# EOS mock tech LEF (v1). Synthetic layer data authored
# for CI; see gen_mock.py and mock/README.md.
VERSION 5.8 ;
BUSBITCHARS "[]" ;
DIVIDERCHAR "/" ;
UNITS
  DATABASE MICRONS 2000 ;
END UNITS
MANUFACTURINGGRID 0.005 ;
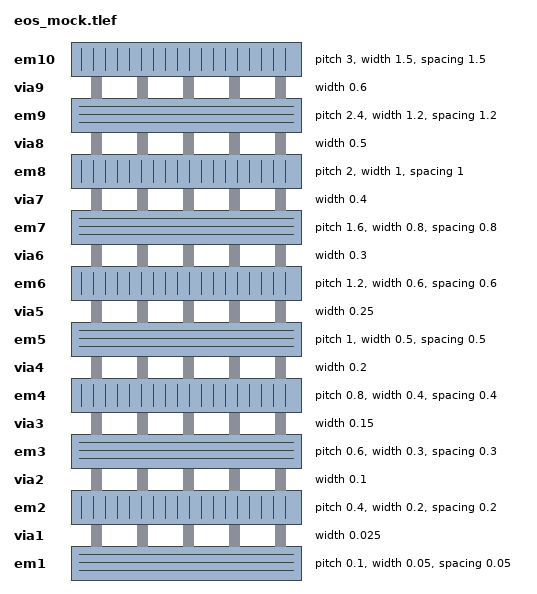
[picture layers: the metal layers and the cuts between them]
LAYER em1
  TYPE ROUTING ;
  DIRECTION HORIZONTAL ;
  PITCH 0.100000 ;
  WIDTH 0.050000 ;
  SPACING 0.050000 ;
  MINWIDTH 0.030000 ;
  AREA 0.005000 ;
  MINSTEP 0.100000 ;
  RESISTANCE RPERSQ 0.200000 ;
  CAPACITANCE CPERSQDIST 0.050000 ;
  EDGECAPACITANCE 0.020000 ;
END em1
LAYER via1
  TYPE CUT ;
  WIDTH 0.025000 ;
END via1
LAYER em2
  TYPE ROUTING ;
  DIRECTION VERTICAL ;
  PITCH 0.400000 ;
  WIDTH 0.200000 ;
  SPACING 0.200000 ;
  MINWIDTH 0.180000 ;
  AREA 0.020000 ;
  MINSTEP 0.100000 ;
  RESISTANCE RPERSQ 0.150000 ;
  CAPACITANCE CPERSQDIST 0.040000 ;
  EDGECAPACITANCE 0.015000 ;
END em2
LAYER via2
  TYPE CUT ;
  WIDTH 0.100000 ;
END via2
LAYER em3
  TYPE ROUTING ;
  DIRECTION HORIZONTAL ;
  PITCH 0.600000 ;
  WIDTH 0.300000 ;
  SPACING 0.300000 ;
  MINWIDTH 0.280000 ;
  AREA 0.030000 ;
  MINSTEP 0.100000 ;
  RESISTANCE RPERSQ 0.100000 ;
  CAPACITANCE CPERSQDIST 0.030000 ;
  EDGECAPACITANCE 0.012000 ;
END em3
LAYER via3
  TYPE CUT ;
  WIDTH 0.150000 ;
END via3
LAYER em4
  TYPE ROUTING ;
  DIRECTION VERTICAL ;
  PITCH 0.800000 ;
  WIDTH 0.400000 ;
  SPACING 0.400000 ;
  MINWIDTH 0.380000 ;
  AREA 0.040000 ;
  MINSTEP 0.100000 ;
  RESISTANCE RPERSQ 0.070000 ;
  CAPACITANCE CPERSQDIST 0.025000 ;
  EDGECAPACITANCE 0.010000 ;
END em4
LAYER via4
  TYPE CUT ;
  WIDTH 0.200000 ;
END via4
LAYER em5
  TYPE ROUTING ;
  DIRECTION HORIZONTAL ;
  PITCH 1.000000 ;
  WIDTH 0.500000 ;
  SPACING 0.500000 ;
  MINWIDTH 0.480000 ;
  AREA 0.050000 ;
  MINSTEP 0.100000 ;
  RESISTANCE RPERSQ 0.050000 ;
  CAPACITANCE CPERSQDIST 0.020000 ;
  EDGECAPACITANCE 0.008000 ;
END em5
LAYER via5
  TYPE CUT ;
  WIDTH 0.250000 ;
END via5
LAYER em6
  TYPE ROUTING ;
  DIRECTION VERTICAL ;
  PITCH 1.200000 ;
  WIDTH 0.600000 ;
  SPACING 0.600000 ;
  MINWIDTH 0.580000 ;
  AREA 0.060000 ;
  MINSTEP 0.100000 ;
  RESISTANCE RPERSQ 0.040000 ;
  CAPACITANCE CPERSQDIST 0.018000 ;
  EDGECAPACITANCE 0.007000 ;
END em6
LAYER via6
  TYPE CUT ;
  WIDTH 0.300000 ;
END via6
LAYER em7
  TYPE ROUTING ;
  DIRECTION HORIZONTAL ;
  PITCH 1.600000 ;
  WIDTH 0.800000 ;
  SPACING 0.800000 ;
  MINWIDTH 0.780000 ;
  AREA 0.080000 ;
  MINSTEP 0.100000 ;
  RESISTANCE RPERSQ 0.030000 ;
  CAPACITANCE CPERSQDIST 0.015000 ;
  EDGECAPACITANCE 0.006000 ;
END em7
LAYER via7
  TYPE CUT ;
  WIDTH 0.400000 ;
END via7
LAYER em8
  TYPE ROUTING ;
  DIRECTION VERTICAL ;
  PITCH 2.000000 ;
  WIDTH 1.000000 ;
  SPACING 1.000000 ;
  MINWIDTH 0.980000 ;
  AREA 0.100000 ;
  MINSTEP 0.100000 ;
  RESISTANCE RPERSQ 0.025000 ;
  CAPACITANCE CPERSQDIST 0.012000 ;
  EDGECAPACITANCE 0.005000 ;
END em8
LAYER via8
  TYPE CUT ;
  WIDTH 0.500000 ;
END via8
LAYER em9
  TYPE ROUTING ;
  DIRECTION HORIZONTAL ;
  PITCH 2.400000 ;
  WIDTH 1.200000 ;
  SPACING 1.200000 ;
  MINWIDTH 1.180000 ;
  AREA 0.120000 ;
  MINSTEP 0.100000 ;
  RESISTANCE RPERSQ 0.020000 ;
  CAPACITANCE CPERSQDIST 0.010000 ;
  EDGECAPACITANCE 0.004000 ;
END em9
LAYER via9
  TYPE CUT ;
  WIDTH 0.600000 ;
END via9
LAYER em10
  TYPE ROUTING ;
  DIRECTION VERTICAL ;
  PITCH 3.000000 ;
  WIDTH 1.500000 ;
  SPACING 1.500000 ;
  MINWIDTH 1.480000 ;
  AREA 0.150000 ;
  MINSTEP 0.100000 ;
  RESISTANCE RPERSQ 0.015000 ;
  CAPACITANCE CPERSQDIST 0.008000 ;
  EDGECAPACITANCE 0.003000 ;
END em10
VIA VIA12
  LAYER em1 ;
    RECT -0.025000 -0.025000 0.025000 0.025000 ;
  LAYER via1 ;
    RECT -0.012500 -0.012500 0.012500 0.012500 ;
  LAYER em2 ;
    RECT -0.100000 -0.100000 0.100000 0.100000 ;
END VIA12
VIA VIA23
  LAYER em2 ;
    RECT -0.100000 -0.100000 0.100000 0.100000 ;
  LAYER via2 ;
    RECT -0.050000 -0.050000 0.050000 0.050000 ;
  LAYER em3 ;
    RECT -0.150000 -0.150000 0.150000 0.150000 ;
END VIA23
VIA VIA34
  LAYER em3 ;
    RECT -0.150000 -0.150000 0.150000 0.150000 ;
  LAYER via3 ;
    RECT -0.075000 -0.075000 0.075000 0.075000 ;
  LAYER em4 ;
    RECT -0.200000 -0.200000 0.200000 0.200000 ;
END VIA34
VIA VIA45
  LAYER em4 ;
    RECT -0.200000 -0.200000 0.200000 0.200000 ;
  LAYER via4 ;
    RECT -0.100000 -0.100000 0.100000 0.100000 ;
  LAYER em5 ;
    RECT -0.250000 -0.250000 0.250000 0.250000 ;
END VIA45
VIA VIA56
  LAYER em5 ;
    RECT -0.250000 -0.250000 0.250000 0.250000 ;
  LAYER via5 ;
    RECT -0.125000 -0.125000 0.125000 0.125000 ;
  LAYER em6 ;
    RECT -0.300000 -0.300000 0.300000 0.300000 ;
END VIA56
VIA VIA67
  LAYER em6 ;
    RECT -0.300000 -0.300000 0.300000 0.300000 ;
  LAYER via6 ;
    RECT -0.150000 -0.150000 0.150000 0.150000 ;
  LAYER em7 ;
    RECT -0.400000 -0.400000 0.400000 0.400000 ;
END VIA67
VIA VIA78
  LAYER em7 ;
    RECT -0.400000 -0.400000 0.400000 0.400000 ;
  LAYER via7 ;
    RECT -0.200000 -0.200000 0.200000 0.200000 ;
  LAYER em8 ;
    RECT -0.500000 -0.500000 0.500000 0.500000 ;
END VIA78
VIA VIA89
  LAYER em8 ;
    RECT -0.500000 -0.500000 0.500000 0.500000 ;
  LAYER via8 ;
    RECT -0.250000 -0.250000 0.250000 0.250000 ;
  LAYER em9 ;
    RECT -0.600000 -0.600000 0.600000 0.600000 ;
END VIA89
VIA VIA910
  LAYER em9 ;
    RECT -0.600000 -0.600000 0.600000 0.600000 ;
  LAYER via9 ;
    RECT -0.300000 -0.300000 0.300000 0.300000 ;
  LAYER em10 ;
    RECT -0.750000 -0.750000 0.750000 0.750000 ;
END VIA910
END LIBRARY
